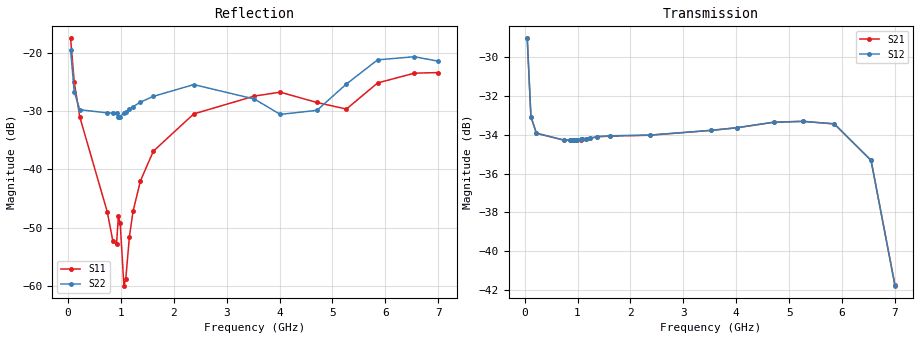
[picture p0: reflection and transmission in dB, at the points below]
! Integrated Device Technology
! Corporate Headquarters
! 6024 Silver Creek Valley Road
! San Jose, CA 95138  USA
! Phone:  1-408-284-8200
! Toll Free:  1-800-223-1366
! Webpage:  http://www.idt.com/
! Timing and RF Division
! 515 Groton Road, Suite 102
! Westford, MA 01886-6024
! Device:  F2258
! Description: Voltage Variable RF Attenuator
! Frequency:  50.0 -  6000.00 MHz
! Package:  3x3 mm Thin QFN Plastic Package: 16 pin
! Ports:  2 RF, 2 DC
!  Pin  1  = NC
!  Pin  2  = NC
!  Pin  3  = RF2  = Port 2
!  Pin  4  = GND
!  Pin  5  = Vdd
!  Pin  6  = NC
!  Pin  7  = VCTRL
!  Pin  8  = NC
!  Pin  9  = GND
!  Pin 10  = RF1  = Port 1
!  Pin 11  = NC
!  Pin 12  = NC
!  Pin 13  = NC
!  Pin 14  = NC
!  Pin 15  = NC
!  Pin 16  = NC
! Vcntrl:  1.870 Volts
! Vdd:  +3.300 Volts
! Current:  1.159 mA
! Data:  The device was measured on a the F2258 evaluation board which has
!  individual transmission lines to the RF pins.  Data was collected
!  using a calibrated network analyzer.  The evaluation board was
!  de-embedded using a TRL calibration technique.
!  The reference plane is the edge of the package pin.
! Misc:  SN 10
!  Action Tracker AT0285
! Date Measured:  2014-12-10
! Date:  2016-01-13  MJV
! Note:
!  Integrated Device Technology supplies this data as a sample of measured
!  data at the package pin for this product.  Your particular data for this
!  product may vary.
!  Data was taken at 25 degrees C.
!  Integrated Device Technology reserves the right to change this data at anytime.
!Freq_(GHz)  S11M_(dB)  S11P_(deg)  S21M_(dB)  S21P_(deg)  S12M_(dB)  S12P_(deg)  S22M_(dB)  S22P_(deg)
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# GHz S dB R 50
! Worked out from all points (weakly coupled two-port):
!   201 points, 50 MHz to 7 GHz, reference 50 ohm
!   highest |S21| = -29.02 dB at 50 MHz (marker M1); lowest = -41.7 dB at 7 GHz (marker M2)
!   lowest |S11| = -60.0 dB at 1.058 GHz (marker M3), VSWR 1.00, Z = 49.9 + j0.0458 ohm
!   |S11| at or under -10 dB: start of sweep to end of sweep
!   |S22| runs from -31.3 to -19.5 dB; largest |S21 - S12| = 6.9e-05
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0.05  -17.55 -110.8  -29.02 -63.7  -29.02 -63.7  -19.53 -101.2
0.1195  -25.11 -106.5  -33.07 -33.8  -33.06 -33.8  -26.74 -67.4
0.22375  -31.03 -110.1  -33.92 -19.7  -33.92 -19.7  -29.80 -39.6
0.745  -47.37 -140.3  -34.28 -9.4  -34.27 -9.4  -30.33 -3.6
0.84925  -52.33 -172.0  -34.28 -9.1  -34.27 -9.1  -30.35 -1.8
0.91875  -52.90 148.2  -34.26 -9.0  -34.26 -9.0  -30.35 -1.9
0.9535  -48.04 -160.0  -34.28 -9.0  -34.28 -9.0  -31.12 2.7
0.98825  -49.28 -172.2  -34.26 -8.9  -34.26 -8.9  -30.96 1.5
1.05775  -59.98 152.7  -34.26 -8.9  -34.24 -8.9  -30.34 2.3
1.0925  -58.90 109.5  -34.24 -8.9  -34.23 -8.9  -30.26 2.4
1.162  -51.57 64.1  -34.21 -9.0  -34.21 -9.0  -29.71 2.5
1.2315  -47.19 43.0  -34.19 -9.1  -34.18 -9.1  -29.26 2.5
1.3705  -41.99 35.0  -34.10 -9.7  -34.09 -9.7  -28.49 3.0
1.61375  -36.91 31.7  -34.07 -11.1  -34.05 -11.2  -27.50 2.5
2.37825  -30.51 47.5  -34.02 -15.3  -34.01 -15.4  -25.48 4.8
3.525  -27.45 91.4  -33.77 -22.6  -33.77 -22.6  -27.96 22.3
4.0115  -26.78 104.4  -33.64 -26.4  -33.63 -26.4  -30.59 28.2
4.7065  -28.55 95.5  -33.35 -32.2  -33.35 -32.2  -29.90 8.3
5.2625  -29.68 53.9  -33.30 -38.3  -33.31 -38.3  -25.39 -14.7
5.85325  -25.20 29.6  -33.44 -48.5  -33.43 -48.5  -21.23 -23.9
6.54825  -23.52 44.9  -35.32 -67.4  -35.32 -67.5  -20.70 -54.2
7  -23.42 84.3  -41.75 -64.2  -41.79 -63.8  -21.47 -125.1
